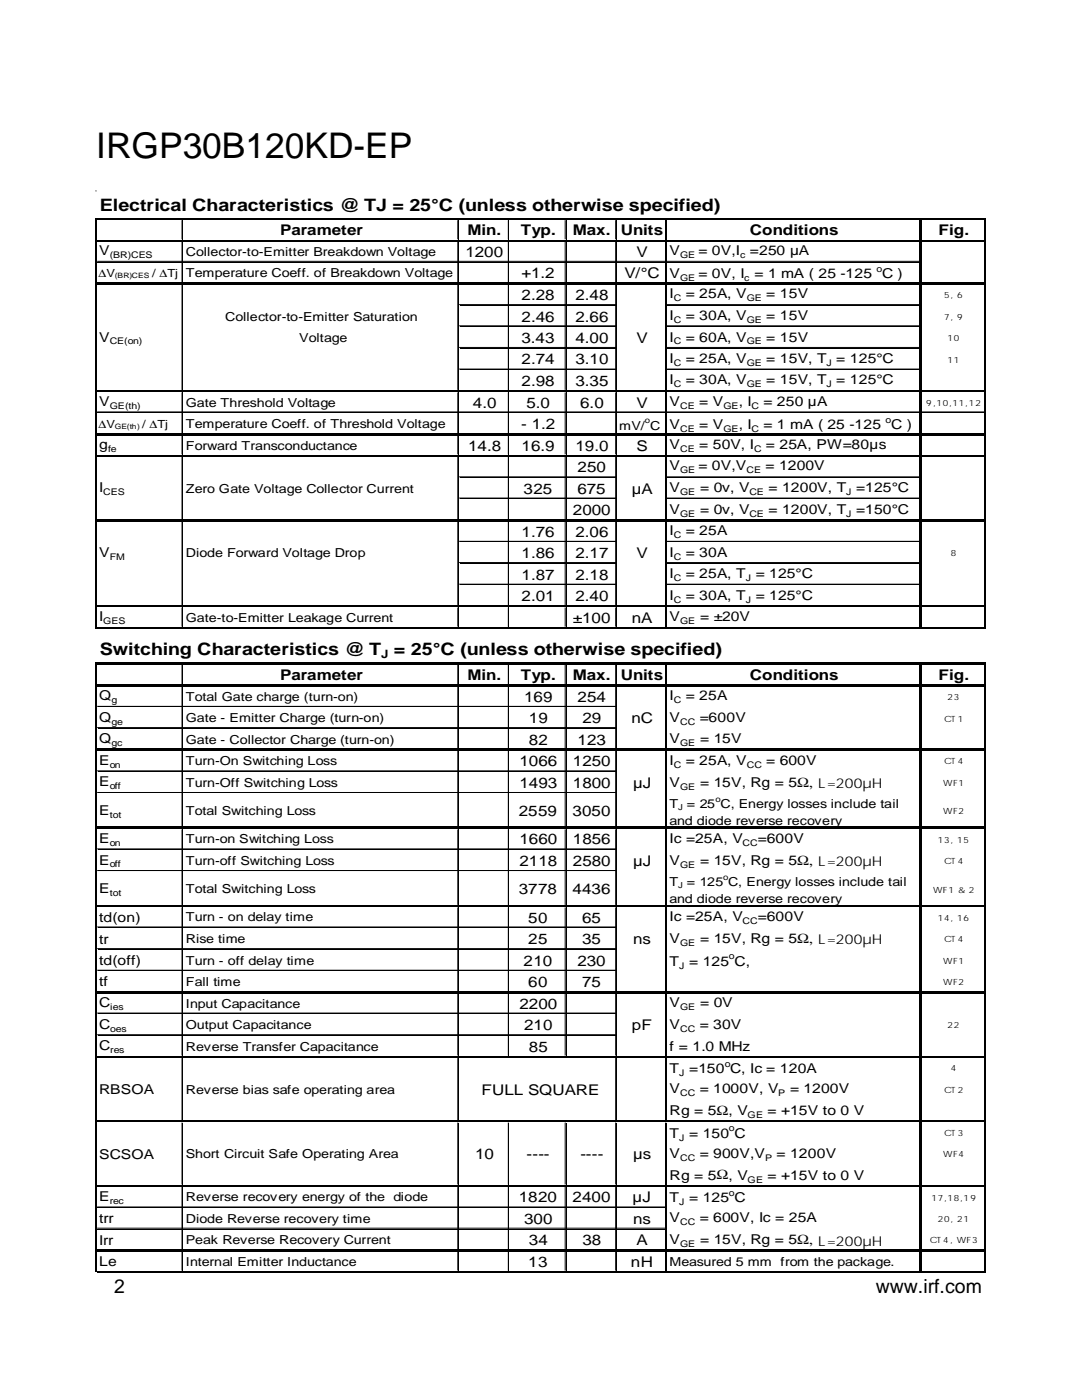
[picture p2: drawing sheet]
<svg xmlns="http://www.w3.org/2000/svg" width="216mm" height="279mm" viewBox="0 0 216 279" stroke-linecap="round" stroke-linejoin="round" font-family="sans-serif">
<defs><g id="words">
<text font-size="7.1" x="19.2" y="31.5">IRGP30B120KD-EP</text>
<g font-size="3.9">
<text x="22.8" y="258.1">2</text>
<text x="174.8" y="258.1">www.irf.com</text>
</g>
<g font-size="3.4">
<text x="19.9" y="42.2">Electrical Characteristics @ TJ = 25°C (unless otherwise specified)</text>
<text x="19.9" y="130.8">Switching Characteristics @ T</text>
<text x="78.6" y="130.8">= 25°C (unless otherwise specified)</text>
</g>
<g font-size="2.9">
<text x="55.9" y="46.9">Parameter</text>
<text x="93.3" y="46.9">Min.</text>
<text x="103.9" y="46.9">Typ.</text>
<text x="114.3" y="46.9">Max. Units</text>
<text x="149.6" y="46.9">Conditions</text>
<text x="187.3" y="46.9">Fig.</text>
<text x="92.9" y="51.3">1200</text>
<text x="127" y="51.3">V</text>
<text x="104.1" y="55.5">+1.2</text>
<text x="104.1" y="59.9">2.28</text>
<text x="114.8" y="59.9">2.48</text>
<text x="124.6" y="55.5">V/°C</text>
<text x="104.1" y="64.2">2.46</text>
<text x="114.8" y="64.2">2.66</text>
<text x="104.1" y="68.5">3.43</text>
<text x="114.8" y="68.5">4.00</text>
<text x="127" y="68.5">V</text>
<text x="104.1" y="72.7">2.74</text>
<text x="104.1" y="77">2.98</text>
<text x="114.8" y="72.7">3.10</text>
<text x="114.8" y="77">3.35</text>
<text x="94.3" y="81.4">4.0</text>
<text x="105.1" y="81.4">5.0</text>
<text x="115.7" y="81.4">6.0</text>
<text x="127" y="81.4">V</text>
<text x="93.4" y="89.9">14.8</text>
<text x="104" y="85.6">- 1.2</text>
<text x="104.1" y="89.9">16.9</text>
<text x="114.8" y="89.9">19.0</text>
<text x="127" y="89.9">S</text>
<text x="115.2" y="94.2">250</text>
<text x="104.5" y="98.6">325</text>
<text x="115.2" y="98.6">675</text>
<text x="126.1" y="98.6">µA</text>
<text x="104.1" y="107.1">1.76</text>
<text x="114.3" y="102.8">2000</text>
<text x="114.8" y="107.1">2.06</text>
<text x="104.1" y="111.4">1.86</text>
<text x="114.8" y="111.4">2.17</text>
<text x="127" y="111.4">V</text>
<text x="104.1" y="115.7">1.87</text>
<text x="104.1" y="120">2.01</text>
<text x="114.8" y="115.7">2.18</text>
<text x="114.8" y="120">2.40</text>
<text x="114.3" y="124.3">±100</text>
<text x="126.1" y="124.3">nA</text>
<text x="55.9" y="135.7">Parameter</text>
<text x="93.3" y="135.7">Min.</text>
<text x="103.9" y="135.7">Typ.</text>
<text x="114.3" y="135.7">Max. Units</text>
<text x="149.6" y="135.7">Conditions</text>
<text x="187.3" y="135.7">Fig.</text>
<text x="104.6" y="140">169</text>
<text x="115.2" y="140">254</text>
<text x="105.5" y="144.4">19</text>
<text x="105.5" y="148.7">82</text>
<text x="115.2" y="148.7">123</text>
<text x="116.2" y="144.4">29</text>
<text x="126" y="144.4">nC</text>
<text x="103.6" y="152.9">1066</text>
<text x="114.3" y="152.9">1250</text>
<text x="103.6" y="157.2">1493</text>
<text x="114.3" y="157.2">1800</text>
<text x="126.3" y="157.2">µJ</text>
<text x="103.5" y="162.9">2559</text>
<text x="114.2" y="162.9">3050</text>
<text x="103.6" y="168.5">1660</text>
<text x="103.6" y="172.8">2118</text>
<text x="114.3" y="168.5">1856</text>
<text x="114.3" y="172.8">2580</text>
<text x="126.3" y="172.8">µJ</text>
<text x="103.5" y="178.5">3778</text>
<text x="114.2" y="178.5">4436</text>
<text x="105.4" y="184.1">50</text>
<text x="116.2" y="184.1">65</text>
<text x="105.4" y="188.4">25</text>
<text x="116.2" y="188.4">35</text>
<text x="126.3" y="188.4">ns</text>
<text x="104.5" y="192.7">210</text>
<text x="105.4" y="197">60</text>
<text x="115.2" y="192.7">230</text>
<text x="116.2" y="197">75</text>
<text x="103.6" y="201.3">2200</text>
<text x="104.6" y="205.6">210</text>
<text x="105.5" y="209.9">85</text>
<text x="126.1" y="205.6">pF</text>
<text x="96.1" y="218.4">FULL SQUARE</text>
<text x="94.8" y="231.4">10</text>
<text x="105.1" y="231.4">----</text>
<text x="115.8" y="231.4">----</text>
<text x="126.3" y="231.4">µs</text>
<text x="103.5" y="239.9">1820</text>
<text x="114.2" y="239.9">2400</text>
<text x="126.2" y="239.9">µJ</text>
<text x="104.6" y="244.3">300</text>
<text x="126.3" y="244.3">ns</text>
<text x="105.5" y="248.5">34</text>
<text x="116.2" y="248.5">38</text>
<text x="127" y="248.5">A</text>
<text x="105.4" y="252.8">13</text>
<text x="125.9" y="252.8">nH</text>
</g>
<g font-size="2.7">
<text x="19.8" y="51">V</text>
<text x="133.6" y="51">V</text>
<text x="139.4" y="51">= 0V,I</text>
<text x="149.6" y="51">=250 µA</text>
<text x="133.6" y="55.5">V</text>
<text x="133.6" y="59.5">I</text>
<text x="136.8" y="59.5">= 25A, V</text>
<text x="139.4" y="55.5">= 0V, I</text>
<text x="150.5" y="55.5">= 1 mA ( 25 -125</text>
<text x="152.9" y="59.5">= 15V</text>
<text x="176" y="55.5">C )</text>
<text x="133.6" y="63.8">I</text>
<text x="136.8" y="63.8">= 30A, V</text>
<text x="152.9" y="63.8">= 15V</text>
<text x="19.8" y="68.2">V</text>
<text x="133.6" y="68.2">I</text>
<text x="136.8" y="68.2">= 60A, V</text>
<text x="152.9" y="68.2">= 15V</text>
<text x="133.6" y="72.5">I</text>
<text x="133.6" y="76.7">I</text>
<text x="136.8" y="72.5">= 25A, V</text>
<text x="136.8" y="76.7">= 30A, V</text>
<text x="152.9" y="72.5">= 15V, T</text>
<text x="152.9" y="76.7">= 15V, T</text>
<text x="166.9" y="72.5">= 125°C</text>
<text x="166.9" y="76.7">= 125°C</text>
<text x="19.8" y="81">V</text>
<text x="133.6" y="81">V</text>
<text x="139.5" y="81">= V</text>
<text x="147.4" y="81">, I</text>
<text x="152.3" y="81">= 250 µA</text>
<text x="19.8" y="89.7">g</text>
<text x="133.6" y="85.6">V</text>
<text x="133.6" y="89.7">V</text>
<text x="139.5" y="85.6">= V</text>
<text x="139.5" y="89.7">= 50V, I</text>
<text x="147.4" y="85.6">, I</text>
<text x="152.3" y="85.6">= 1 mA ( 25 -125</text>
<text x="152.8" y="89.7">= 25A, PW=80µs</text>
<text x="177.8" y="85.6">C )</text>
<text x="133.6" y="93.9">V</text>
<text x="139.4" y="93.9">= 0V,V</text>
<text x="152.7" y="93.9">= 1200V</text>
<text x="19.8" y="98.2">I</text>
<text x="133.6" y="98.2">V</text>
<text x="139.7" y="98.2">= 0v, V</text>
<text x="153.3" y="98.2">= 1200V, T</text>
<text x="170.9" y="98.2">=125°C</text>
<text x="133.6" y="102.5">V</text>
<text x="133.6" y="106.8">I</text>
<text x="136.8" y="106.8">= 25A</text>
<text x="139.7" y="102.5">= 0v, V</text>
<text x="153.3" y="102.5">= 1200V, T</text>
<text x="170.9" y="102.5">=150°C</text>
<text x="19.8" y="111.1">V</text>
<text x="133.6" y="111.1">I</text>
<text x="136.8" y="111.1">= 30A</text>
<text x="133.6" y="115.4">I</text>
<text x="133.6" y="119.7">I</text>
<text x="136.8" y="115.4">= 25A, T</text>
<text x="136.8" y="119.7">= 30A, T</text>
<text x="150.8" y="115.4">= 125°C</text>
<text x="150.8" y="119.7">= 125°C</text>
<text x="19.8" y="124">I</text>
<text x="133.6" y="124">V</text>
<text x="139.7" y="124">= ±20V</text>
<text x="19.8" y="139.7">Q</text>
<text x="133.6" y="139.7">I</text>
<text x="136.8" y="139.7">= 25A</text>
<text x="19.8" y="144">Q</text>
<text x="19.8" y="148.3">Q</text>
<text x="133.6" y="144">V</text>
<text x="133.6" y="148.3">V</text>
<text x="139.6" y="144">=600V</text>
<text x="139.7" y="148.3">= 15V</text>
<text x="19.8" y="152.7">E</text>
<text x="133.6" y="152.7">I</text>
<text x="136.8" y="152.7">= 25A, V</text>
<text x="152.9" y="152.7">= 600V</text>
<text x="19.8" y="156.9">E</text>
<text x="133.6" y="157.1">V</text>
<text x="139.7" y="157.1">= 15V, Rg = 5Ω, L=200µH</text>
<text x="19.8" y="162.6">E</text>
<text x="19.8" y="168.2">E</text>
<text x="19.8" y="172.6">E</text>
<text x="133.6" y="168.2">Ic =25A, V</text>
<text x="133.6" y="172.6">V</text>
<text x="139.7" y="172.6">= 15V, Rg = 5Ω, L=200µH</text>
<text x="151.2" y="168.2">=600V</text>
<text x="19.8" y="178.1">E</text>
<text x="19.8" y="184">td(on)</text>
<text x="133.6" y="183.8">Ic =25A, V</text>
<text x="151.2" y="183.8">=600V</text>
<text x="19.8" y="188.3">tr</text>
<text x="133.6" y="188.2">V</text>
<text x="139.7" y="188.2">= 15V, Rg = 5Ω, L=200µH</text>
<text x="19.8" y="192.5">td(off)</text>
<text x="19.8" y="196.8">tf</text>
<text x="133.6" y="192.7">T</text>
<text x="137.5" y="192.7">= 125 C,</text>
<text x="19.8" y="201">C</text>
<text x="133.6" y="201">V</text>
<text x="139.7" y="201">= 0V</text>
<text x="19.8" y="205.3">C</text>
<text x="19.8" y="209.5">C</text>
<text x="133.6" y="205.3">V</text>
<text x="133.6" y="209.7">f = 1.0 MHz</text>
<text x="139.6" y="205.3">= 30V</text>
<text x="133.6" y="214.1">T</text>
<text x="137.5" y="214.1">=150 C, Ic = 120A</text>
<text x="19.8" y="218.4">RBSOA</text>
<text x="133.6" y="218.2">V</text>
<text x="139.6" y="218.2">= 1000V, V</text>
<text x="157.6" y="218.2">= 1200V</text>
<text x="133.6" y="222.6">Rg = 5Ω, V</text>
<text x="133.6" y="227.1">T</text>
<text x="137.5" y="227.1">= 150 C</text>
<text x="153.2" y="222.6">= +15V to 0 V</text>
<text x="19.8" y="231.2">SCSOA</text>
<text x="133.6" y="231.1">V</text>
<text x="139.6" y="231.1">= 900V,V</text>
<text x="154.9" y="231.1">= 1200V</text>
<text x="19.8" y="239.6">E</text>
<text x="133.6" y="235.5">Rg = 5Ω, V</text>
<text x="133.6" y="239.9">T</text>
<text x="137.5" y="239.9">= 125 C</text>
<text x="153.2" y="235.5">= +15V to 0 V</text>
<text x="19.8" y="244.1">trr</text>
<text x="133.6" y="243.9">V</text>
<text x="139.6" y="243.9">= 600V, Ic = 25A</text>
<text x="19.8" y="248.4">Irr</text>
<text x="133.6" y="248.3">V</text>
<text x="139.7" y="248.3">= 15V, Rg = 5Ω, L=200µH</text>
<text x="19.8" y="252.7">Le</text>
</g>
<g font-size="2.5">
<text x="37.1" y="51.1">Collector-to-Emitter Breakdown Voltage</text>
<text x="37.1" y="55.4">Temperature Coeff. of Breakdown Voltage</text>
<text x="45" y="64">Collector-to-Emitter Saturation</text>
<text x="59.7" y="68.2">Voltage</text>
<text x="37.1" y="81.2">Gate Threshold Voltage</text>
<text x="37.1" y="85.4">Temperature Coeff. of Threshold Voltage</text>
<text x="37.1" y="89.7">Forward Transconductance</text>
<text x="123.5" y="85.8">mV/ C</text>
<text x="37.1" y="98.3">Zero Gate Voltage Collector Current</text>
<text x="37.1" y="111.3">Diode Forward Voltage Drop</text>
<text x="37.1" y="124.1">Gate-to-Emitter Leakage Current</text>
<text x="37.1" y="139.9">Total Gate charge (turn-on)</text>
<text x="37.1" y="144.2">Gate - Emitter Charge (turn-on)</text>
<text x="37.1" y="148.4">Gate - Collector Charge (turn-on)</text>
<text x="37.1" y="152.7">Turn-On Switching Loss</text>
<text x="37.1" y="157.1">Turn-Off Switching Loss</text>
<text x="133.6" y="161.3">T = 25 C, Energy losses include tail</text>
<text x="37.1" y="162.7">Total Switching Loss</text>
<text x="133.6" y="164.6">and diode reverse recovery</text>
<text x="37.1" y="168.3">Turn-on Switching Loss</text>
<text x="37.1" y="172.6">Turn-off Switching Loss</text>
<text x="37.1" y="178.3">Total Switching Loss</text>
<text x="133.6" y="176.9">T = 125 C, Energy losses include tail</text>
<text x="37.1" y="183.9">Turn - on delay time</text>
<text x="133.6" y="180.3">and diode reverse recovery</text>
<text x="37.1" y="188.2">Rise time</text>
<text x="37.1" y="192.5">Turn - off delay time</text>
<text x="37.1" y="196.8">Fall time</text>
<text x="37.1" y="201.1">Input Capacitance</text>
<text x="37.1" y="205.4">Output Capacitance</text>
<text x="37.1" y="209.7">Reverse Transfer Capacitance</text>
<text x="37.1" y="218.3">Reverse bias safe operating area</text>
<text x="37.1" y="231.1">Short Circuit Safe Operating Area</text>
<text x="37.1" y="239.8">Reverse recovery energy of the diode</text>
<text x="37.1" y="244">Diode Reverse recovery time</text>
<text x="37.1" y="248.3">Peak Reverse Recovery Current</text>
<text x="37.1" y="252.6">Internal Emitter Inductance</text>
<text x="133.6" y="252.6">Measured 5 mm from the package.</text>
</g>
<text font-size="2.3" x="76" y="131.4">J</text>
<g font-size="2.2">
<text x="19.6" y="55.3">∆V</text>
<text x="30.4" y="55.4">/ ∆Tj</text>
<text x="19.6" y="85.3">∆V</text>
<text x="28.4" y="85.4">/ ∆Tj</text>
</g>
<g font-size="1.8">
<text x="21.9" y="51.6">(BR)CES</text>
<text x="135.7" y="51.6">GE</text>
<text x="147.7" y="51.6">c</text>
<text x="135.7" y="56.1">GE</text>
<text x="148.5" y="56.1">c</text>
<text x="174.9" y="54.3">o</text>
<text x="134.5" y="60.1">C</text>
<text x="134.5" y="64.4">C</text>
<text x="149" y="60.1">GE</text>
<text x="149" y="64.4">GE</text>
<text x="21.9" y="68.7">CE(on)</text>
<text x="134.5" y="68.7">C</text>
<text x="149" y="68.7">GE</text>
<text x="134.5" y="73.1">C</text>
<text x="134.5" y="77.3">C</text>
<text x="149" y="73.1">GE</text>
<text x="149" y="77.3">GE</text>
<text x="164.9" y="73.1">J</text>
<text x="164.9" y="77.3">J</text>
<text x="21.9" y="81.6">GE(th)</text>
<text x="135.7" y="81.6">CE</text>
<text x="144.4" y="81.6">GE</text>
<text x="149.9" y="81.6">C</text>
<text x="135.7" y="86.2">CE</text>
<text x="144.4" y="86.2">GE</text>
<text x="149.9" y="86.2">C</text>
<text x="176.7" y="84.3">o</text>
<text x="21.6" y="90.2">fe</text>
<text x="135.7" y="90.2">CE</text>
<text x="135.7" y="94.5">GE</text>
<text x="148.9" y="94.5">CE</text>
<text x="150.5" y="90.2">C</text>
<text x="20.6" y="98.8">CES</text>
<text x="135.7" y="98.8">GE</text>
<text x="149.5" y="98.8">CE</text>
<text x="168.8" y="98.8">J</text>
<text x="134.5" y="107.4">C</text>
<text x="135.7" y="103.1">GE</text>
<text x="149.5" y="103.1">CE</text>
<text x="168.8" y="103.1">J</text>
<text x="21.9" y="111.7">FM</text>
<text x="134.5" y="111.7">C</text>
<text x="134.5" y="116">C</text>
<text x="148.8" y="116">J</text>
<text x="20.6" y="124.5">GES</text>
<text x="134.5" y="120.3">C</text>
<text x="135.7" y="124.5">GE</text>
<text x="148.8" y="120.3">J</text>
<text x="22.3" y="140.3">g</text>
<text x="134.5" y="140.3">C</text>
<text x="22.3" y="144.6">ge</text>
<text x="22.3" y="148.9">gc</text>
<text x="135.7" y="144.6">CC</text>
<text x="135.7" y="148.9">GE</text>
<text x="21.9" y="153.2">on</text>
<text x="134.5" y="153.2">C</text>
<text x="149" y="153.2">CC</text>
<text x="21.9" y="157.5">off</text>
<text x="135.7" y="157.6">GE</text>
<text x="21.9" y="163.2">tot</text>
<text x="21.9" y="168.8">on</text>
<text x="21.9" y="173.1">off</text>
<text x="135.7" y="173.2">GE</text>
<text x="148.2" y="168.8">CC</text>
<text x="21.9" y="178.7">tot</text>
<text x="148.2" y="184.4">CC</text>
<text x="135.7" y="188.8">GE</text>
<text x="145.5" y="191.4">o</text>
<text x="135.6" y="193.3">J</text>
<text x="22" y="201.6">ies</text>
<text x="135.7" y="201.6">GE</text>
<text x="22" y="205.9">oes</text>
<text x="135.7" y="205.9">CC</text>
<text x="22" y="210.1">res</text>
<text x="135.6" y="214.7">J</text>
<text x="144.6" y="212.9">o</text>
<text x="135.7" y="218.8">CC</text>
<text x="155.3" y="218.8">P</text>
<text x="135.6" y="227.7">J</text>
<text x="145.5" y="225.7">o</text>
<text x="149.2" y="223.2">GE</text>
<text x="135.7" y="231.6">CC</text>
<text x="152.7" y="231.6">P</text>
<text x="145.5" y="238.7">o</text>
<text x="149.2" y="236.1">GE</text>
<text x="21.9" y="240.2">rec</text>
<text x="135.6" y="240.5">J</text>
<text x="135.7" y="244.5">CC</text>
<text x="135.7" y="248.9">GE</text>
</g>
<g font-size="1.7">
<text x="188.4" y="59.5">5, 6</text>
<text x="188.4" y="63.8">7, 9</text>
<text x="189.1" y="68.1">10</text>
<text x="189.1" y="72.4">11</text>
<text x="184.8" y="80.9">9,10,11,12</text>
<text x="189.7" y="111">8</text>
<text x="189.1" y="139.7">23</text>
<text x="188.4" y="144">CT1</text>
<text x="188.4" y="152.6">CT4</text>
<text x="188.2" y="156.9">WF1</text>
<text x="188.2" y="162.5">WF2</text>
<text x="187.1" y="168.1">13, 15</text>
<text x="188.4" y="172.5">CT4</text>
<text x="186.2" y="178.1">WF1 &amp; 2</text>
<text x="187.1" y="183.7">14, 16</text>
<text x="188.4" y="188">CT4</text>
<text x="188.2" y="192.4">WF1</text>
<text x="188.2" y="196.6">WF2</text>
<text x="189.1" y="205.2">22</text>
<text x="189.7" y="213.8">4</text>
<text x="188.4" y="218.1">CT2</text>
<text x="188.4" y="226.7">CT3</text>
<text x="188.2" y="231">WF4</text>
<text x="185.8" y="239.6">17,18,19</text>
<text x="187.1" y="243.8">20, 21</text>
<text x="185.5" y="248.2">CT4, WF3</text>
</g>
<g font-size="1.6">
<text x="128.7" y="84.4">o</text>
<text x="135.3" y="161.7">J</text>
<text x="142.7" y="160">o</text>
<text x="135.3" y="177.3">J</text>
<text x="144.3" y="175.6">o</text>
</g>
<g font-size="1.5">
<text x="22.9" y="55.5">(BR)CES</text>
<text x="22.9" y="85.6">GE(th)</text>
</g>
</g></defs>
<g fill="none" stroke="#000" stroke-width=".2">
<path d="M19 38.1h.1M19.4 52.2h164.1M19.5 52.3h163.9M36.3 43.9v3.9M36.3 48.3v8.1M36.3 56.8v21M36.5 43.9v3.9M36.5 48.3v8M36.5 56.9v20.9M91.4 43.9v3.9M91.4 48.3v8.1M91.4 56.8v21"/>
<path d="M91.5 43.9v3.9M91.5 48.3v8M91.5 56.9v20.9M101.4 43.9v3.9M101.4 48.3v8.1M101.4 56.8v21M101.5 43.9v3.9M101.5 48.3v8M101.5 56.9v20.9M112.8 43.9v3.9M112.8 48.3v8.1M112.8 56.8v21"/>
<path d="M112.9 43.9v3.9M112.9 48.3v8M112.9 56.9v20.9M122.9 43.9v3.9M122.9 48.3v8.1M122.9 56.8v21M122.9 48.3v8M122.9 56.9v20.9M132.8 43.9v3.9M132.8 48.3v8.1M132.8 56.8v21M36.3 78.3v8.1"/>
<path d="M36.5 78.3v8.1M91.4 78.3v8.1M91.5 78.3v8.1M91.6 60.8h31.5M91.6 65h31.5M91.6 69.3h31.5M91.6 73.7h31.5M91.7 60.9h31.3M91.7 65.2h31.3M91.7 69.5h31.3M91.7 73.7h31.3M101.4 78.3v8.1"/>
<path d="M101.5 78.3v8.1M112.8 78.3v8.1M112.9 78.3v8.1M122.9 78.3v8.1M132.8 78.3v8.1M133.1 60.8h50.4M133.1 65h50.4M133.1 69.3h50.4M133.1 73.7h50.4M133.2 60.9h50.2M133.2 65.2h50.2M133.2 69.5h50.2"/>
<path d="M133.2 73.7h50.2M19.4 82.2h164.1M19.5 82.4h163.9M36.3 86.9v3.8M36.3 91.2v12.4M36.5 87v3.7M36.5 91.2v12.3M91.4 86.9v3.8M91.4 91.2v12.4M91.5 87v3.7M91.5 91.2v12.3M91.6 95.2h31.5"/>
<path d="M91.6 99.4h31.5M91.7 95.2h31.3M91.7 99.5h31.3M101.4 86.9v3.8M101.4 91.2v12.4M101.5 87v3.7M101.5 91.2v12.3M112.8 86.9v3.8M112.8 91.2v12.4M112.9 87v3.7M112.9 91.2v12.3M122.9 86.9v3.8"/>
<path d="M122.9 91.2v12.4M122.9 87v3.7M122.9 91.2v12.3M132.8 86.9v3.8M132.8 91.2v12.4M133.1 95.2h50.4M133.1 99.4h50.4M133.2 95.2h50.2M133.2 99.5h50.2M184 82.2h12.4M184.1 82.4h12.2M36.3 104.1v16.6"/>
<path d="M36.5 104.1v16.6M91.4 104.1v16.6M91.5 104.1v16.6M91.6 108h31.5M91.6 112.3h31.5M91.6 116.6h31.5M91.7 108.1h31.3M91.7 112.4h31.3M91.7 116.7h31.3M101.4 104.1v16.6M101.5 104.1v16.6M112.8 104.1v16.6"/>
<path d="M112.9 104.1v16.6M122.9 104.1v16.6M132.8 104.1v16.6M133.1 108h50.4M133.1 112.3h50.4M133.1 116.6h50.4M133.2 108.1h50.2M133.2 112.4h50.2M133.2 116.7h50.2M36.3 121.2v3.9M36.3 132.7v3.9M36.3 137v12.4"/>
<path d="M36.5 121.2v3.9M36.5 132.8v3.7M36.5 137.1v12.3M91.4 121.2v3.9M91.4 132.7v3.9M91.4 137v12.4M91.5 121.2v3.9M91.5 132.8v3.7M91.5 137.1v12.3M101.4 121.2v3.9M101.4 132.7v3.9M101.4 137v12.4"/>
<path d="M101.5 121.2v3.9M101.5 132.8v3.7M101.5 137.1v12.3M112.8 121.2v3.9M112.8 132.7v3.9M112.8 137v12.4M112.9 121.2v3.9M112.9 132.8v3.7M112.9 137.1v12.3M122.9 121.2v3.9M122.9 132.7v3.9M122.9 137v12.4"/>
<path d="M122.9 132.8v3.7M122.9 137.1v12.3M132.8 121.2v3.9M132.8 132.7v3.9M132.8 137v12.4M19.4 141h103.7M19.4 145.2h103.7M19.4 153.8h103.7M19.4 158.2h103.7M19.5 141.1h103.5M19.5 145.4h103.5M19.5 153.9h103.5"/>
<path d="M19.5 158.2h103.5M36.3 149.9v15.1M36.5 149.9v15M91.4 149.9v15.1M91.5 149.9v15M101.4 149.9v15.1M101.5 149.9v15M112.8 149.9v15.1M112.9 149.9v15M122.9 149.9v15.1M122.9 149.9v15M132.8 149.9v15.1"/>
<path d="M19.4 169.4h103.7M19.4 173.7h103.7M19.5 169.5h103.5M19.5 173.8h103.5M36.3 165.5v15.1M36.5 165.5v15.1M91.4 165.5v15.1M91.5 165.5v15.1M101.4 165.5v15.1M101.5 165.5v15.1M112.8 165.5v15.1M112.9 165.5v15.1"/>
<path d="M122.9 165.5v15.1M132.8 165.5v15.1M19.4 185h103.7M19.4 189.3h103.7M19.4 193.6h103.7M19.5 185.1h103.5M19.5 189.4h103.5M19.5 193.7h103.5M36.3 181.1v16.7M36.3 198.3v12.4M36.5 181.1v16.6M36.5 198.3v12.4"/>
<path d="M91.4 181.1v16.7M91.4 198.3v12.4M91.5 181.1v16.6M91.5 198.3v12.4M101.4 181.1v16.7M101.4 198.3v12.4M101.5 181.1v16.6M101.5 198.3v12.4M112.8 181.1v16.7M112.8 198.3v12.4M112.9 181.1v16.6M112.9 198.3v12.4"/>
<path d="M122.9 181.1v16.7M122.9 198.3v12.4M122.9 181.1v16.6M132.8 181.1v16.7M132.8 198.3v12.4M19.4 202.2h103.7M19.4 206.5h103.7M19.5 202.3h103.5M19.5 206.6h103.5M36.3 211.2v12.3M36.5 211.2v12.3M91.4 211.2v12.3"/>
<path d="M91.5 211.2v12.3M122.9 211.2v12.3M132.8 211.2v12.3M36.3 224v12.4M36.3 236.9v12.4M36.5 224v12.4M36.5 236.9v12.4M91.4 224v12.4M91.4 236.9v12.4M91.5 224v12.4M91.5 236.9v12.4M101.4 224v12.4"/>
<path d="M101.4 236.9v12.4M101.5 224v12.4M101.5 236.9v12.4M112.8 224v12.4M112.8 236.9v12.4M112.9 224v12.4M112.9 236.9v12.4M122.9 224v12.4M122.9 236.9v12.4M132.8 224v12.4M132.8 236.9v12.4M19.4 240.9h113.7"/>
<path d="M19.4 245.1h113.7M19.5 241h113.6M19.5 245.3h113.6M36.3 249.8v3.8M36.5 249.9v3.7M91.4 249.8v3.8M91.5 249.9v3.7M101.4 249.8v3.8M101.5 249.9v3.7M112.8 249.8v3.8M112.9 249.9v3.7M122.9 249.8v3.8"/>
<path d="M122.9 249.9v3.7M132.8 249.8v3.8"/>
</g>
<g fill="none" stroke="#000" stroke-width=".25">
<path d="M133 43.9v3.9M133 48.3v8M133 56.9v20.9M133 78.3v8.1M133 87v3.7M133 91.2v12.3M133 104.1v16.6M133 121.2v3.9M133 132.8v3.7M133 137.1v12.3M133 149.9v15M133 165.5v15.1"/>
<path d="M133 181.1v16.6M133 198.3v12.4M133 211.2v12.3M133 224v12.4M133 236.9v12.4M19.5 253.8h177.3M133 249.9v3.7"/>
</g>
<g fill="none" stroke="#000" stroke-width=".34">
<path d="M19.2 43.5v82M19.5 43.7h177.3M19.5 48h177.3M196.6 43.9v81.6M19.5 78.1h177.3M19.5 90.9h177.3M19.2 132.2v121.7M19.5 121h177.3M19.5 125.3h177.3M196.6 132.8v121.1M19.5 180.8h177.3M19.5 210.9h177.3"/>
<path d="M19.5 223.8h177.3M19.5 236.6h177.3"/>
</g>
<path d="M183.5 43.9h.5v81.6h-.5zM183.5 132.8h.5v121.1h-.5z" fill="#000"/>
<path d="M19.5 56.6h177.3M19.5 86.7h177.3M19.5 103.8h177.3M19.5 132.5h177.3M19.5 136.8h177.3M19.5 149.6h177.3M19.5 165.2h177.3M19.5 198h177.3M19.5 249.6h177.3" fill="none" stroke="#000" stroke-width=".42"/>
<use href="#words"/>
</svg>
